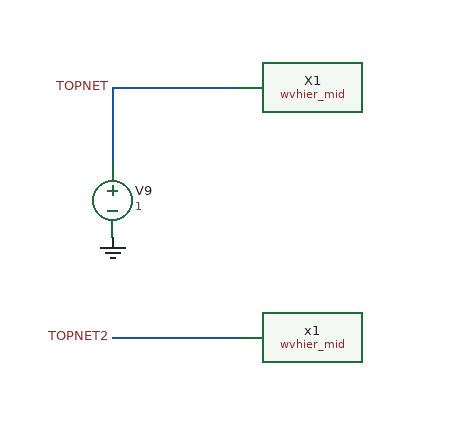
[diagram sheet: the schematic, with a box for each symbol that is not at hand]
v {xschem version=3.4.4 file_version=1.2}
G {}
V {}
S {}
E {}
N 0 0 100 0 {}
N 0 0 0 60 {}
N 0 200 100 200 {}
C {devices/lab_pin.sym} 0 0 0 0 {name=l1 lab=TOPNET}
C {wvhier_mid.sym} 120 0 0 0 {name=X1}
C {devices/vsource.sym} 0 90 0 0 {name=V9 value=1}
C {devices/gnd.sym} 0 120 0 0 {name=l2 lab=0}
C {devices/lab_pin.sym} 0 200 0 0 {name=l3 lab=TOPNET2}
C {wvhier_mid.sym} 120 200 0 0 {name=x1}
